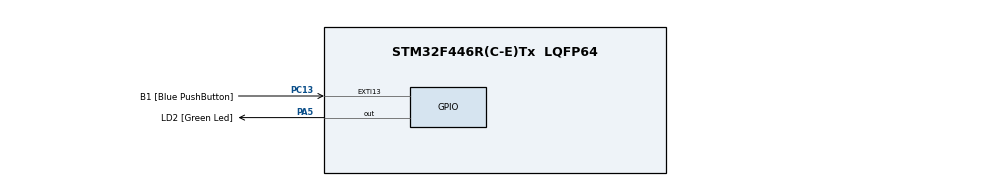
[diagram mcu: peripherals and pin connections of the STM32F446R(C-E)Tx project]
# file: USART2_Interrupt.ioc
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Mcu.Family=STM32F4
Mcu.Name=STM32F446R(C-E)Tx
Mcu.Package=LQFP64
NVIC.PriorityGroup=NVIC_PRIORITYGROUP_0
PA13.GPIO_Label=TMS
PA13.Signal=SYS_JTMS-SWDIO
PA14.GPIO_Label=TCK
PA14.Signal=SYS_JTCK-SWCLK
PA2.GPIO_Label=USART_TX
PA2.Signal=USART2_TX
PA3.GPIO_Label=USART_RX
PA3.Signal=USART2_RX
PA5.GPIO_Label=LD2 [Green Led]
PA5.Signal=GPIO_Output
PB3.GPIO_Label=SWO
PB3.Signal=SYS_JTDO-SWO
PC13.GPIO_Label=B1 [Blue PushButton]
PC13.GPIO_ModeDefaultEXTI=GPIO_MODE_IT_FALLING
PC13.Signal=GPXTI13
PC14-OSC32_IN.Signal=RCC_OSC32_IN
PC15-OSC32_OUT.Signal=RCC_OSC32_OUT
PH0-OSC_IN.Signal=RCC_OSC_IN
PH1-OSC_OUT.Signal=RCC_OSC_OUT
ProjectManager.HeapSize=0x200
ProjectManager.StackSize=0x400
ProjectManager.TargetToolchain=CMake
RCC.AHBFreq_Value=84000000
RCC.APB1CLKDivider=RCC_HCLK_DIV2
RCC.APB1Freq_Value=42000000
RCC.APB1TimFreq_Value=84000000
RCC.APB2Freq_Value=84000000
RCC.APB2TimFreq_Value=84000000
RCC.CortexFreq_Value=84000000
RCC.FLatency-AdvancedSettings=FLASH_LATENCY_2
RCC.HCLKFreq_Value=84000000
RCC.HSE_VALUE=8000000
RCC.HSI_VALUE=16000000
RCC.LSE_VALUE=32768
RCC.PLLN=336
RCC.PLLP=RCC_PLLP_DIV4
RCC.SYSCLKFreq_VALUE=84000000
RCC.SYSCLKSource=RCC_SYSCLKSOURCE_PLLCLK
RCC.USBFreq_Value=168000000
RCC.VCOOutputFreq_Value=336000000
board=NUCLEO-F446RE

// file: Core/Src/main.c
#include "main.h"
#include "stm32f446xx.h"
#include "usart2_interrupt.h"

int main(void)
{

  USART_Init();
  Enable_Interrupt();
  Send_String("UART ready\r\n");

  while (1)
  {
	  if(rx_ready)
	  {
		  Send_Char(rx_char);
		  rx_ready = 0;
	  }

  }

}

void SystemClock_Config(void)
{
  RCC_OscInitTypeDef RCC_OscInitStruct = {0};
  RCC_ClkInitTypeDef RCC_ClkInitStruct = {0};

  /** Configure the main internal regulator output voltage
  */
  __HAL_RCC_PWR_CLK_ENABLE();
  __HAL_PWR_VOLTAGESCALING_CONFIG(PWR_REGULATOR_VOLTAGE_SCALE3);

  /** Initializes the RCC Oscillators according to the specified parameters
  * in the RCC_OscInitTypeDef structure.
  */
  RCC_OscInitStruct.OscillatorType = RCC_OSCILLATORTYPE_HSI;
  RCC_OscInitStruct.HSIState = RCC_HSI_ON;
  RCC_OscInitStruct.HSICalibrationValue = RCC_HSICALIBRATION_DEFAULT;
  RCC_OscInitStruct.PLL.PLLState = RCC_PLL_NONE;
  if (HAL_RCC_OscConfig(&RCC_OscInitStruct) != HAL_OK)
  {
    Error_Handler();
  }

  /** Initializes the CPU, AHB and APB buses clocks
  */
  RCC_ClkInitStruct.ClockType = RCC_CLOCKTYPE_HCLK|RCC_CLOCKTYPE_SYSCLK
                              |RCC_CLOCKTYPE_PCLK1|RCC_CLOCKTYPE_PCLK2;
  RCC_ClkInitStruct.SYSCLKSource = RCC_SYSCLKSOURCE_HSI;
  RCC_ClkInitStruct.AHBCLKDivider = RCC_SYSCLK_DIV1;
  RCC_ClkInitStruct.APB1CLKDivider = RCC_HCLK_DIV1;
  RCC_ClkInitStruct.APB2CLKDivider = RCC_HCLK_DIV1;

  if (HAL_RCC_ClockConfig(&RCC_ClkInitStruct, FLASH_LATENCY_0) != HAL_OK)
  {
    Error_Handler();
  }
}

void Error_Handler(void)
{
  __disable_irq();
  while (1)
  {
  }
}
